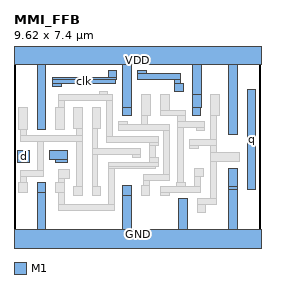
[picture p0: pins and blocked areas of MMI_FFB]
MACRO MMI_FFB
	CLASS CORE ;
	FOREIGN MMI_FFB 0 0 ;
	SIZE 9.62 BY 7.4 ;
	SYMMETRY X Y ;
	SITE CORE1 ;
	PIN d
		DIRECTION input ;
		USE SIGNAL ;
		PORT
			LAYER M1 ;
			RECT 0.145 3.085 0.595 3.565 ;
		END
		AntennaGateArea 0.2484 ;
	END d
	PIN GND
		DIRECTION inout ;
		USE GROUND ;
		PORT
			LAYER M1 ;
			RECT 0.9 1.925 1.24 2.305 ;
			LAYER M1 ;
			RECT 0.905 0.5 1.245 1.925 ;
			LAYER M1 ;
			RECT 4.23 1.81 4.57 2.19 ;
			LAYER M1 ;
			RECT 8.36 2.18 8.7 2.88 ;
			LAYER M1 ;
			RECT 8.36 2.04 8.705 2.18 ;
			LAYER M1 ;
			RECT 4.235 0.5 4.575 1.81 ;
			LAYER M1 ;
			RECT 6.41 0.5 6.75 1.685 ;
			LAYER M1 ;
			RECT 8.365 0.5 8.705 2.04 ;
			LAYER M1 ;
			RECT 0.005 -0.5 9.625 0.5 ;
		END
	END GND
	PIN q
		DIRECTION output ;
		USE SIGNAL ;
		PORT
			LAYER M1 ;
			RECT 9.08 2.04 9.42 5.945 ;
		END
		AntennaDiffArea 1.3248 ;
	END q
	PIN VDD
		DIRECTION inout ;
		USE POWER ;
		PORT
			LAYER M1 ;
			RECT 0.005 6.9 9.625 7.9 ;
			LAYER M1 ;
			RECT 0.9 4.395 1.24 6.9 ;
			LAYER M1 ;
			RECT 4.235 5.25 4.575 6.9 ;
			LAYER M1 ;
			RECT 6.945 5.75 7.285 6.9 ;
			LAYER M1 ;
			RECT 4.23 4.91 4.575 5.25 ;
			LAYER M1 ;
			RECT 6.94 5.25 7.285 5.75 ;
			LAYER M1 ;
			RECT 6.94 4.91 7.28 5.25 ;
			LAYER M1 ;
			RECT 8.36 4.185 8.7 6.9 ;
		END
	END VDD
	PIN clk
		DIRECTION input ;
		USE CLOCK ;
		PORT
			LAYER M1 ;
			RECT 3.665 6.4 4.005 6.67 ;
			LAYER M1 ;
			RECT 1.51 6.33 4.005 6.4 ;
			LAYER M1 ;
			RECT 4.805 6.565 5.145 6.67 ;
			LAYER M1 ;
			RECT 4.805 6.335 6.5 6.565 ;
			LAYER M1 ;
			RECT 4.805 6.33 5.145 6.335 ;
			LAYER M1 ;
			RECT 1.51 6.17 3.95 6.33 ;
			LAYER M1 ;
			RECT 6.27 6.185 6.5 6.335 ;
			LAYER M1 ;
			RECT 1.51 6.06 1.85 6.17 ;
			LAYER M1 ;
			RECT 6.27 5.845 6.61 6.185 ;
			LAYER M1 ;
			RECT 1.38 3.215 2.08 3.555 ;
			LAYER M1 ;
			RECT 1.63 3.105 2.08 3.215 ;
		END
		AntennaGateArea 0.6408 ;
	END clk
	OBS
		LAYER M1 ;
		RECT 0.18 4.395 0.52 5.235 ;
		LAYER M1 ;
		RECT 3.32 5.735 3.66 5.875 ;
		LAYER M1 ;
		RECT 1.73 5.505 3.84 5.735 ;
		LAYER M1 ;
		RECT 1.73 5.235 1.96 5.505 ;
		LAYER M1 ;
		RECT 1.62 4.395 1.96 5.235 ;
		LAYER M1 ;
		RECT 2.32 4.405 2.66 5.245 ;
		LAYER M1 ;
		RECT 3.04 4.405 3.38 5.245 ;
		LAYER M1 ;
		RECT 0.24 4.145 0.47 4.395 ;
		LAYER M1 ;
		RECT 2.425 4.145 2.655 4.405 ;
		LAYER M1 ;
		RECT 0.24 3.915 2.655 4.145 ;
		LAYER M1 ;
		RECT 0.91 2.77 1.14 3.915 ;
		LAYER M1 ;
		RECT 1.83 2.82 2.17 2.825 ;
		LAYER M1 ;
		RECT 0.25 2.54 1.14 2.77 ;
		LAYER M1 ;
		RECT 0.25 2.305 0.48 2.54 ;
		LAYER M1 ;
		RECT 1.73 2.485 2.17 2.82 ;
		LAYER M1 ;
		RECT 1.73 2.305 1.96 2.485 ;
		LAYER M1 ;
		RECT 0.18 1.925 0.52 2.305 ;
		LAYER M1 ;
		RECT 1.62 1.925 1.96 2.305 ;
		LAYER M1 ;
		RECT 2.425 2.15 2.655 3.915 ;
		LAYER M1 ;
		RECT 3.04 3.645 3.27 4.405 ;
		LAYER M1 ;
		RECT 3.61 4.11 3.84 5.505 ;
		LAYER M1 ;
		RECT 4.98 4.91 5.32 5.75 ;
		LAYER M1 ;
		RECT 5.7 5.14 6.04 5.75 ;
		LAYER M1 ;
		RECT 5.7 4.91 6.68 5.14 ;
		LAYER M1 ;
		RECT 7.66 4.91 8 5.75 ;
		LAYER M1 ;
		RECT 4.07 4.57 4.41 4.68 ;
		LAYER M1 ;
		RECT 4.985 4.57 5.215 4.91 ;
		LAYER M1 ;
		RECT 6.375 4.68 6.68 4.91 ;
		LAYER M1 ;
		RECT 4.07 4.34 6.07 4.57 ;
		LAYER M1 ;
		RECT 3.61 4.105 5.515 4.11 ;
		LAYER M1 ;
		RECT 3.61 3.88 5.61 4.105 ;
		LAYER M1 ;
		RECT 5.27 3.765 5.61 3.88 ;
		LAYER M1 ;
		RECT 4.6 3.645 4.94 3.65 ;
		LAYER M1 ;
		RECT 3.04 3.415 4.94 3.645 ;
		LAYER M1 ;
		RECT 3.04 2.15 3.27 3.415 ;
		LAYER M1 ;
		RECT 4.6 3.31 4.94 3.415 ;
		LAYER M1 ;
		RECT 5.285 3.3 5.515 3.765 ;
		LAYER M1 ;
		RECT 5.27 3.08 5.61 3.3 ;
		LAYER M1 ;
		RECT 3.68 2.96 5.61 3.08 ;
		LAYER M1 ;
		RECT 3.68 2.85 5.515 2.96 ;
		LAYER M1 ;
		RECT 1.73 1.445 1.96 1.925 ;
		LAYER M1 ;
		RECT 2.32 1.81 2.66 2.15 ;
		LAYER M1 ;
		RECT 3.04 1.81 3.38 2.15 ;
		LAYER M1 ;
		RECT 3.68 1.445 3.91 2.85 ;
		LAYER M1 ;
		RECT 5.84 2.615 6.07 4.34 ;
		LAYER M1 ;
		RECT 5.06 2.38 6.07 2.615 ;
		LAYER M1 ;
		RECT 6.375 4.45 7.43 4.68 ;
		LAYER M1 ;
		RECT 5.06 2.19 5.29 2.38 ;
		LAYER M1 ;
		RECT 6.375 2.305 6.605 4.45 ;
		LAYER M1 ;
		RECT 7.09 4.34 7.43 4.45 ;
		LAYER M1 ;
		RECT 7.66 3.985 7.89 4.91 ;
		LAYER M1 ;
		RECT 6.835 3.755 7.89 3.985 ;
		LAYER M1 ;
		RECT 6.835 3.645 7.175 3.755 ;
		LAYER M1 ;
		RECT 7.66 3.475 7.89 3.755 ;
		LAYER M1 ;
		RECT 7.66 3.135 8.765 3.475 ;
		LAYER M1 ;
		RECT 7.03 2.54 7.37 2.88 ;
		LAYER M1 ;
		RECT 4.95 1.81 5.29 2.19 ;
		LAYER M1 ;
		RECT 6.33 2.15 6.67 2.305 ;
		LAYER M1 ;
		RECT 7.03 2.15 7.26 2.54 ;
		LAYER M1 ;
		RECT 5.71 1.92 7.26 2.15 ;
		LAYER M1 ;
		RECT 5.71 1.81 6.05 1.92 ;
		LAYER M1 ;
		RECT 1.73 1.215 3.91 1.445 ;
		LAYER M1 ;
		RECT 7.66 1.685 7.89 3.135 ;
		LAYER M1 ;
		RECT 7.13 1.455 7.89 1.685 ;
		LAYER M1 ;
		RECT 7.13 1.145 7.47 1.455 ;
	END
END MMI_FFB
